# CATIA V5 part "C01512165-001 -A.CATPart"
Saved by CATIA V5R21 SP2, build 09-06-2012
Part number: C01512165-001
Revision: ---
Description: PROPRIETARY NOTICE (do not delete / modify)  ***************************************************************************************************  LA SOCIETE EN COMMANDITE  AIRBUS CANADA  ("AIRBUS CANADA")  PAR  L'INTERMEDIAIRE  DE  SES  DIVISIONS  ET/OU  FILIALES  CORPORATIVES,  FOURNIT  LES PRESENTES  INFORMATIONS  AU  GOUVERNEMENT  A  TITRE CONFIDENTIEL. CES  INFORMATIONS ONT UNE TENEUR CONFIDENTIELLE,  AVEC DROITS DE PROPRIETE,  ET NOUS LES CONSIDERONS  EXCLUS  DE   L'APPLICATION  DE  LA LOI SUR L'ACCES A L'INFORMATION  (CANADA),  LES  LOIS  SUR  L'ACCES  A  L'INFORMATION  EUROPEENNES,  LE FREEDOM OF INFORMATION ACT (ETATS-UNIS) ET D'AUTRES LOIS SEMBLABLES. ELLES  PEUVENT  AUSSI  CONSTITUER DES SECRETS INDUSTRIELS DE NOTRE SOCIETE OU DE TIERCES PARTIES. LA DIVULGATION  PUBLIQUE  DE CES  INFORMATIONS NUIRAIT A AIRBUS CANADA OU A DES TIERCES PARTIES.  CES INFORMATIONS PEUVENT EGALEMENT CONTENIR  DES DONNEES QUI SONT CONTROLEE PAR DES LOIS DE CONTROLE DES EXPORTATIONS DU CANADA, L’EUROPE OU LES  ETATS-  UNIS. TOUTE EXPORTATION OU REEXPORTATION DE DONNEES CONTROLEES SANS AUTORISATION EST STRICTEMENT INTERDITE.  TOUTE INTENTION DE LES DIVULGUER EN TOUT OU EN PARTIE DEVRA ETRE SIGNIFIEE A L'AVANCE ET PAR ECRIT AU VICE-  PRESIDENT, SERVICES JURIDIQUES ET CONFORMITE ET SECRETAIRE CORPORATIF D'AIRBUS CANADA.    AIRBUS CANADA LIMITED PARTNERSHIP  ("AIRBUS CANADA"),  BY ITS AFFILIATES AND/OR SUBSIDIARIES, PROVIDES THIS  INFORMATION TO THE GOVERNMENT IN CONFIDENCE. THIS IS PROPRIETARY CONFIDENTIAL INFORMATION WHICH WE CONSIDER  EXCLUDED  FROM  THE  APPLICATION OF THE ACCESS TO INFORMATION ACT (CANADA),  THE FREEDOM OF INFORMATION ACT  (U.S.A.),  THE ACCESS TO INFORMATION LAWS IN EUROPE, AND OTHER SIMILAR LEGISLATION. AND MAY ALSO CONSTITUTE  TRADE SECRETS OF OUR  COMPANY OR THIRD PARTIES.  PUBLIC  RELEASE  OF  THIS INFORMATION  WOULD BE HARMFUL TO  AIRBUS CANADA OR THIRD PARTIES.  THIS  INFORMATION  MAY  ALSO  CONTAIN DATA THAT IS CONTROLLED BY CANADIAN,  EUROPEAN, OR U.S.A. EXPORT CONTROL LAWS. ANY UNAUTHORIZED EXPORT OR RE-EXPORT OF ANY EXPORT CONTROLLED DATA  IS STRICTLY PROHIBITED  ANY INTENTION TO DISCLOSE SUCH INFORMATION,  OR  PART THEREOF,  MUST BE NOTIFIED IN  ADVANCE AND IN WRITING TO THE VICE PRESIDENT, LEGAL AND COMPLIANCE AND CORPORATE SECRETARY OF AIRBUS CANADA.        LES RENSEIGNEMENTS,  LES DONNEES  ET  DESSINS  TECHNIQUES  DIVULGUES  DANS  LES PRESENTES SONT LA PROPRIETE  EXCLUSIVE DE LA SOCIETE EN COMMANDITE AIRBUS CANADA ("AIRBUS CANADA") OU COMPORTENT DES DROITS DE PROPRIETE  APPARTENANT  A  AUTRUI ET NE PEUVENT ETRE DIVULGUES  A  QUICONQUE  NI  UTILISES PAR QUI QUE CE SOIT SANS LE  CONSENTEMENT  ECRIT  D’AIRBUS  CANADA.  LE DETENTEUR DES  PRESENTES  S'ENGAGE, DANS TOUTES CIRCONSTANCES, A  GARDER CONFIDENTIELS LES DONNEES ET DESSINS TECHNIQUES QU'ELLES CONTIENNENT.   CE QUI PRECEDE NE S'APPLIQUE  PAS  AUX PERSONNES  QUI  ONT DES DROITS DE PROPRIETE SUR CES RENSEIGNEMENTS,  DONNEES TECHNIQUES ET DESSINS  DANS LA MESURE OU CES DROITS EXISTENT.    THE INFORMATION,  TECHNICAL DATA  AND  DESIGNS DISCLOSED HEREIN ARE THE EXCLUSIVE PROPERTY OF AIRBUS CANADA  LIMITED PARTNERSHIP  ("AIRBUS CANADA")  OR  CONTAIN PROPRIETARY RIGHTS OF OTHERS  AND ARE NOT TO BE USED OR  DISCLOSED  TO  OTHERS WITHOUT THE WRITTEN CONSENT OF AIRBUS CANADA.  THE RECIPIENT OF THIS DOCUMENT, BY ITS  RETENTION  AND  USE  AGREES TO  HOLD  IN  CONFIDENCE  THE  TECHNICAL DATA AND DESIGNS CONTAINED HEREIN. THE  FOREGOING SHALL NOT APPLY TO PERSONS HAVING PROPRIETARY RIGHTS TO SUCH INFORMATION,  TECHNICAL DATA OR SUCH  DESIGNS TO THE EXTENT THAT SUCH RIGHTS EXIST.    Copyright 2020 Airbus Canada Limited Partnership. All Rights Reserved.  ***********************************
Property "Title": "AXIS, STOP, FWD PASS DR"
Property "Dataset Type": "DETAIL"
Property "Supplier Name And CAGE Code": "AIRBUS CANADA LIMITED PARTNERSHIP L0J48"
Property "Major Supplier Code": "LP"
Property "3D Only": "Y"
Property "Material Form": "BAR - ROUND"
Property "Finish Code": "T002"
Property "PCCN": "2"
Property "Organization": "DESIGN"
Property "Design Authority Program": "BD-500"
Property "Color Coded": "N/A"
Property "Thickness": 0
Property "Inside Diameter": 0
Property "Outside Diameter": 1
Property "Length": 0
Property "Width": 0
Property "Wall": 0
Property "Wire Gauge": "-"
Property "Alloy": "6AL-4V"
Property "Final Condition": "ANL"
Property "Density": "N/A"
Property "Form": "N/A"
Property "Grade/Composition": "N/A"
Property "Material Class": "N/A"
Property "Mesh Cell Size": "N/A"
Property "Standard Spec Die": "N/A"
Property "Type": "N/A"
Property "Style": "N/A"
Property "MFG Process": "MACHINED"
Property "Material Specification Production": "AMS4928"
Property "Material Description Production": "TITANIUM"
Property "Dimensions": "DIMENSIONS ARE IN INCHES"
Property "Roughness": "ALL MACHINED SURFACES 125 Ra MAX"
Property "Eng. Tolerances": "LINEAR .XX= +/-.03; .XXX= +/-.010; ANGULAR= +/-0.5 DEG"
Property "Tool Design Tolerances": "LINEAR .X= +/-.06; .XX= +/-.015; .XXX= +/-.005; .XXXX= +/-.001; ANGULAR= +/-0.5 DEG"
Property "Project": "BA"
Publications: "PartBody", "Extract.1_Datum_A", "Extract.1_Datum_B", "Extract.1_Datum_C"
Material "TI-6AL-4V": density 4428.78 kg/m3, Young's modulus 1.11695e+11 Pa, Poisson ratio 0.31
Bounding box of the stored display mesh (mm): x -195.199 to 0, y -7.928 to 7.928, z -7.928 to 7.928
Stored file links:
  C:\Users\CQQZ006\Desktop\A220钢钛件\舱门\C01512165-001\C01512165-001 -A.CATPart

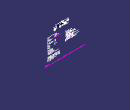
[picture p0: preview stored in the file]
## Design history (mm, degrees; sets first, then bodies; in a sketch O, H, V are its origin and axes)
AxisSystem1 "Absolute Axis System": origin (0, 0, 0), X (1, 0, 0), Y (0, 1, 0), Z (0, 0, 1)
Part_3D_Annotations1 "CATTPSSet"
AxisSystem2 "Copy of Absolute Axis System": origin (0, 0, 0), X (1, 0, 0), Y (0, 1, 0), Z (0, 0, 1)
Set1 "Geometrical Set for 3D Annotations"
  Set2 "No Show Geometry"
    Extract1 "Extract.1_Datum_A"
    Extract2 "Extract.1_Datum_B"
    Extract3 "Extract.1_Datum_C"
  Set3 "Surfaces for 3D Annotations"
    Plane1: type Offset, RefPlane face of Shaft1 from Sketch1.L3, Offset 2.54, reversed
    Split1: ToCut {extract ExtractElem face of Shaft1 from Sketch1.L9}, Cutting Plane1
Body1 (main body)
  Sketch1 on zx-plane, origin (0, 0, 0), H (-1, 0, 0), V (0, 0, 1)
    line L1 (0, 5.5563) -> (0, 7.62)
    line L2 (47.244, 7.9286) -> (60.706, 7.9286)
    line L3 (183.769, 6.3411) -> (183.769, 5.8103)
    construction line L4 (-6.4289, -7.9286) -> (34.6372, -7.9286)
    line L5 (183.769, 6.3411) -> (176.403, 6.3411)
    construction line L6 (148.8263, -6.3411) -> (203.575, -6.3411)
    line L7 (169.799, 5.5563) -> (0, 5.5563)
    line L8 (169.799, 5.5563) -> (171.6321, 2.3813)
    point P6 (169.799, 5.5563)
    line L9 (184.023, 5.5563) -> (195.199, 5.5563)
    line L10 (195.199, 5.5563) -> (195.199, 2.3813)
    line L11 (171.6321, 2.3813) -> (195.199, 2.3813)
    arc A1 centre (184.023, 5.8103) radius 0.254 from (183.769, 5.8103) to (184.023, 5.5563) ccw
    construction line L12 (160.8874, -5.5563) -> (177.3117, -5.5563)
    line L13 (176.149, 7.62) -> (176.149, 6.5951)
    arc A2 centre (176.403, 6.5951) radius 0.254 from (176.149, 6.5951) to (176.403, 6.3411) ccw
    line L14 (176.149, 7.62) -> (63.4887, 7.62)
    arc A3 centre (63.4887, 20.32) radius 12.7 from (63.4887, 7.62) to (60.706, 7.9286) cw
    point P21 (60.706, 7.9286)
    construction line L15 (58.674, 9.1823) -> (58.674, 3.3825)
    line L16 (0, 7.62) -> (44.4613, 7.62)
    arc A4 centre (44.4613, 20.32) radius 12.7 from (44.4613, 7.62) to (47.244, 7.9286) ccw
    point P27 (47.244, 7.9286)
    construction line L17 (49.276, 10.0366) -> (49.276, 1.9278)
    distance L4 L2 = 15.8572
    distance L6 L5 = 12.6822
    angle L7 L8 = 120
    distance L7 H = 5.5563
    distance L7 L2 = 2.3724 (reference)
    radius A1 = 0.254
    distance L9 L12 = 11.1125
    distance L10 L3 = 11.43
    radius A2 = 0.254
    distance L13 V = 176.149
    distance L13 L3 = 7.62
    distance L11 H = 2.3813
    distance L13 P6 = 6.35
    distance L14 H = 7.62
    radius A3 = 12.7
    distance L15 P21 = 2.032
    distance P21 V = 60.706
    radius A4 = 12.7
    distance P27 L17 = 2.032
    distance H L16 = 7.62
    distance L17 V = 49.276
    vertical: L1 V, L3 V, L10 V, L13 V, L15 V, L17 V
    coincidence: O L1, P27 L2, P27 A4
    horizontal: L4 H, L5 H, L6 H, L7 H, L9 H, L11 H, L12 H, L14 H, L16 H
    symmetry: L2 L4 H, L5 L6 H, L9 L12 H
    tangency: A1 L3, A1 L9, A2 L13, A2 L5, A3 L14, A4 L16
  Shaft1: profile Sketch1, axis Sketch1.H, angle 360
  Body2
  Assemble1: tool Body2
  Body3
  Assemble2: tool Body3
  Chamfer1: length 1.016, angle 45, on edge [face of Shaft1 from Sketch1.L9 | face of Shaft1 from Sketch1.L10]; edge [face of Shaft1 from Sketch1.L1 | face of Shaft1 from Sketch1.L16]
  Body4
  Assemble3: tool Body4
  Sketch2 on xy-plane, origin (0, 0, 0), H (1, 0, 0), V (0, 1, 0)
    circle A1 centre (-191.389, 0) radius 1.4097
    point P1 (-191.389, 0)
    reference projected line E1 through (0, 0) direction (-1, 0) from axis of face of Shaft1 from Sketch1.L14
    reference intersected line E2 through (-195.199, 0) direction (0, -1) from face of Shaft1 from Sketch1.L10
    radius A1 = 1.4097
    distance P1 E2 = 3.81
    coincidence: P1 E1
  Pocket1: profile Sketch2, direction (0, 0, -1), through (limit type 6), opposite side through (limit type 6)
